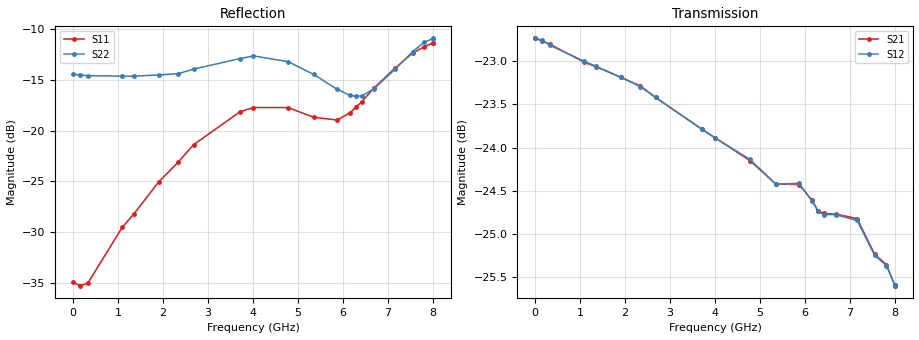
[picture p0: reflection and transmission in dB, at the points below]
! DEVICE ID: PE43712
! File Path: z:\PE43713\PE43713_CHAR_NOM_04292014\AMB\3p300\LS_ATT_21p50dB\PE43713_AMB_3p300V_3p000V_0p000V_LS_ATT_21p50dB_S2P_SN_10_A0139A.s2p
! Serial: 10
! Lot: A0139A
! Temp: 25C
! VDD: 3.300
! VSS: 0.000
! Control_Hi: 3.000
! Control_Lo: 0.000
! Attenuation Step: 21.50dB
! Port 1: RF1
! Port 2: RF2
! ThroughPath:1-2
! IDD: 0.0001470249
! ISS: -1.146e-007
#  Hz  S  RI  R  50
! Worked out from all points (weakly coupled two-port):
!   801 points, 10 MHz to 8.01 GHz, reference 50 ohm
!   highest |S21| = -22.74 dB at 10 MHz (marker M1); lowest = -25.6 dB at 8 GHz (marker M2)
!   lowest |S11| = -35.3 dB at 160 MHz (marker M3), VSWR 1.03, Z = 48.4 + j0.521 ohm
!   |S11| at or under -10 dB: start of sweep to end of sweep
!   |S22| runs from -16.6 to -10.9 dB; largest |S21 - S12| = 0.00026
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1e7  -0.0178 0.000668  0.073 -0.00036  0.073 -0.00034  -0.19 0.00131
1.6e8  -0.0163 0.00538  0.0726 -0.00439  0.0727 -0.00438  -0.1878 0.0126
3.3e8  -0.0148 0.00966  0.0719 -0.00884  0.0718 -0.00875  -0.1854 0.0232
1.1e9  -0.00988 0.032  0.0655 -0.0266  0.0656 -0.0266  -0.1707 0.0735
1.35e9  -0.00629 0.0382  0.0628 -0.0316  0.0628 -0.0317  -0.1637 0.0877
1.91e9  0.00516 0.0558  0.0552 -0.0419  0.0552 -0.0419  -0.1421 0.1238
2.34e9  0.0167 0.068  0.0481 -0.0488  0.0481 -0.0487  -0.1218 0.1473
2.68e9  0.0272 0.0808  0.042 -0.0528  0.042 -0.0528  -0.1042 0.1723
3.71e9  0.0448 0.1155  0.0215 -0.061  0.0214 -0.061  -0.0685 0.2162
4.01e9  0.0472 0.1212  0.0155 -0.062  0.0155 -0.062  -0.0642 0.225
4.78e9  0.0541 0.1182  0.000705 -0.062  0.00072 -0.0621  -0.0418 0.2151
5.35e9  0.0684 0.0943  -0.00919 -0.0594  -0.00917 -0.0594  -0.0198 0.1885
5.87e9  0.0907 0.0671  -0.0183 -0.0572  -0.0183 -0.0573  0.0233 0.1583
6.16e9  0.1086 0.0566  -0.024 -0.0537  -0.0238 -0.0537  0.0549 0.1388
6.29e9  0.1197 0.0527  -0.0251 -0.0523  -0.025 -0.0523  0.0714 0.1294
6.42e9  0.1295 0.0502  -0.0266 -0.0513  -0.0264 -0.0513  0.0873 0.1203
6.68e9  0.1549 0.0465  -0.0304 -0.0491  -0.0303 -0.0491  0.12 0.1064
7.16e9  0.1987 0.0461  -0.0379 -0.0431  -0.0378 -0.043  0.1758 0.098
7.55e9  0.2355 0.0519  -0.0413 -0.0359  -0.0412 -0.0359  0.224 0.1012
7.81e9  0.2536 0.0581  -0.0431 -0.0325  -0.043 -0.0325  0.2518 0.1062
8e9  0.2632 0.0628  -0.0434 -0.0295  -0.0434 -0.0296  0.2643 0.1062
8.01e9  0.2636 0.0634  -0.0435 -0.0295  -0.0434 -0.0295  0.265 0.1062
